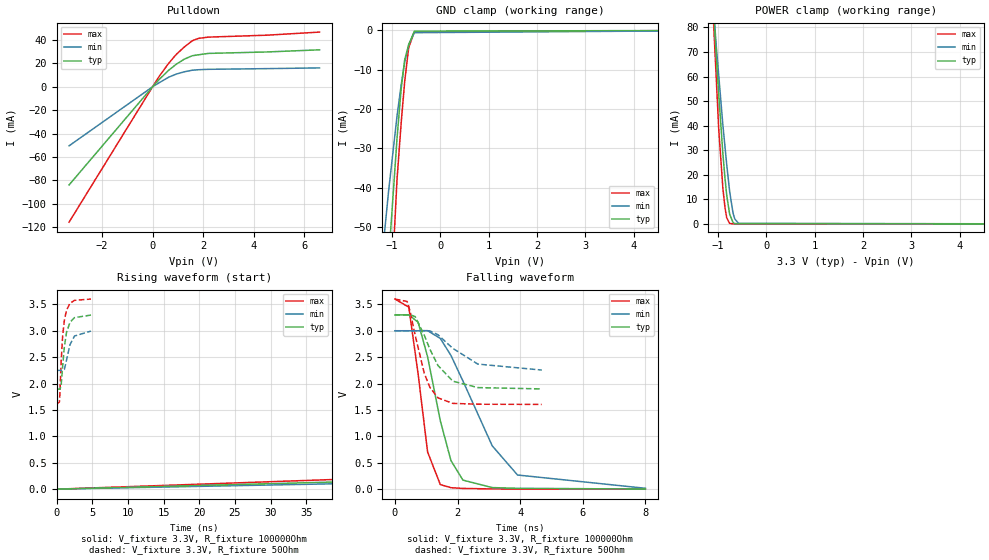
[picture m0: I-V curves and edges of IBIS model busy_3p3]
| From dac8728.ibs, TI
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|   busy_3p3 Model
[Model]   busy_3p3
Model_type   Open_drain
Polarity   Non-Inverting
Vmeas = 1.65
Vref = 3.3
Cref = 10pF
Rref = 100000
|   typ   min   max
|   (nom PVT)   (Fast PVT)   (slow PVT)
|C_comp from frequency method(F=50MHz)
|Average
C_comp   8.636e-12   7.116e-12   1.008e-11
|ON state : BUFFER OUTPUT TURNED LOW
|C_comp   8.804e-12   7.277e-12   1.026e-11
|OFF state: BUFFER IN HIGH IMPEDANCE
|C_comp   8.467e-12   6.956e-12   9.902e-12
|C_comp from L-C Tank method(L=1nH)
|Average
|C_comp   7.915e-12   6.670e-12   9.147e-12
|ON state : BUFFER OUTPUT TURNED LOW
|Resonant Frequency(Hz)   1.780e+09   1.930e+09   1.660e+09
|C_comp   8.003e-12   6.807e-12   9.201e-12
|OFF state: BUFFER IN HIGH IMPEDANCE
|Resonant Frequency(Hz)   1.800e+09   1.970e+09   1.670e+09
|C_comp   7.826e-12   6.533e-12   9.092e-12
| Where nom  PVT is Nominal Process,  3.3V,  33C
|   Fast PVT is Strong Process,   3.6V,  -40C
|   Slow PVT is Weak Process,   3V,  113C
[Voltage Range]   3.3   3   3.6
|Ambient Temperature   25   105   -40
|Junction Temperature
[Temperature Range]   33   113   -40
[Pullup Reference]   3.3   3   3.6
[Pulldown Reference]   0   0   0
[Power Clamp Reference]   3.3   3   3.6
[GND Clamp Reference]   0   0   0
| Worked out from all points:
|   slope of the pulldown table from 0 to 0.495 V, typ, clamps not added: 44 ohm
|   GND clamp passes 1 mA (typ) near -0.60 V on its own axis
|   POWER clamp passes 1 mA (typ) near -0.71 V on its own axis
|   falling waveform, V_fixture 3.3V, R_fixture 100000Ohm: 20-80 % time 725ps typ, 1.43ns min, 436ps max; typ from 3.3 V to 0.003 V
|   rising waveform, V_fixture 3.3V, R_fixture 100000Ohm: 20-80 % time 1.23us typ, 1.47us min, 1.01us max; typ from 0.001 V to 3.3 V
|   falling waveform, V_fixture 3.3V, R_fixture 50Ohm: 20-80 % time 710ps typ, 972ps min, 507ps max; typ from 3.3 V to 1.9 V
|   rising waveform, V_fixture 3.3V, R_fixture 50Ohm: 20-80 % time 708ps typ, 889ps min, 569ps max; typ from 1.9 V to 3.3 V
[Pulldown]
|   Voltage   I(typ)   I(min)   I(max)
-3.3V     -84.11mA   -50.56mA   -116mA
18mV      443.3uA    274.6uA    641.4uA
273.6mV   6.576mA    3.631mA    9.304mA
633.6mV   14.12mA    8.199mA    20.06mA
939.6mV   19.39mA    10.93mA    27.83mA
1.247V    23.62mA    12.83mA    33.99mA
1.566V    26.63mA    14.23mA    39.43mA
1.814V    27.44mA    14.64mA    41.5mA
2.203V    28.63mA    14.99mA    42.59mA
4.5V      29.86mA    15.58mA    44.23mA
6.6V      31.7mA     16.21mA    46.9mA
[GND Clamp]
|   Voltage   I(typ)   I(min)   I(max)
-3.3V     -572.7mA   -387.4mA   -802.2mA
-1.361V   -118.9mA   -77.73mA   -170.9mA
-1.272V   -100mA     -65.91mA   -143mA
-1.184V   -81.73mA   -55mA      -115.6mA
-1.071V   -59.2mA    -40.91mA   -81.77mA
-1.036V   -52.29mA   -37.09mA   -71.86mA
-896.4mV  -27.44mA   -21.78mA   -37.88mA
-811.8mV  -14.96mA   -13.98mA   -23.71mA
-738mV    -7.483mA   -8.126mA   -12.99mA
-655.2mV  -3.679mA   -3.589mA   -4.387mA
-537.9mV  -215.9uA   -600.8uA   -323.7uA
6.6V      0A         0A         0A
[POWER Clamp]
|   Voltage   I(typ)   I(min)   I(max)
-3.3V     869.3mA    734.6mA    1.044A
-1.084V   85.81mA    86.41mA    79.97mA
-1.032V   68.16mA    72.24mA    58.91mA
-982.8mV  52.97mA    60.65mA    38.83mA
-896.4mV  28.7mA     40.32mA    14.56mA
-853.2mV  18.73mA    31.56mA    6.771mA
-817.2mV  11.76mA    24.27mA    2.531mA
-756mV    3.952mA    13.19mA    210.4uA
-687mV    641.4uA    4.545mA    38.04uA
-651mV    146.4uA    2.075mA    32.51uA
-573mV    128.8uA    253uA      20.54uA
6.6V      0A         0A         0A
[Ramp]
R_load = 100000
|   typ   min   max
dV/dt_r   1.97809/1.23136e-06   1.796/1.46732e-06   2.15905/1.00462e-06
dV/dt_f   1.97921/7.27305e-10   1.7988/1.45405e-09   2.15938/4.41656e-10
[Falling Waveform]
V_fixture = 3.3V
V_fixture_min = 3V
V_fixture_max = 3.6V
R_fixture = 100000Ohm
|   Time   V(typ)   V(min)   V(max)
0s        3.3V       3V         3.6V
444ps     3.301V     3V         3.447V
742ps     3.161V     3V         2.182V
1.044ns   2.51V      3.002V     705.3mV
1.45ns    1.297V     2.855V     88.05mV
1.79ns    542.7mV    2.533V     28.73mV
2.172ns   172.7mV    2.05V      15.13mV
3.108ns   30.9mV     821.4mV    5.404mV
3.916ns   17.36mV    269mV      2.781mV
7.998ns   2.988mV    17.76mV    1.029mV
[Rising Waveform]
V_fixture = 3.3V
V_fixture_min = 3V
V_fixture_max = 3.6V
R_fixture = 100000Ohm
|   Time   V(typ)   V(min)   V(max)
0s        1.294mV    1.958mV    1.007mV
165.8ns   576.4mV    432.5mV    782mV
309.5ns   1.012V     774.2mV    1.331V
472.7ns   1.418V     1.108V     1.813V
648.3ns   1.765V     1.408V     2.202V
1.091us   2.361V     1.955V     2.819V
1.674us   2.788V     2.382V     3.212V
2.443us   3.055V     2.677V     3.435V
3.709us   3.223V     2.882V     3.557V
8us       3.298V     2.995V     3.599V
[Falling Waveform]
V_fixture = 3.3V
V_fixture_min = 3V
V_fixture_max = 3.6V
R_fixture = 50Ohm
|   Time   V(typ)   V(min)   V(max)
0s        3.3V       3V         3.6V
392ps     3.3V       3V         3.554V
488ps     3.302V     3V         3.366V
648ps     3.268V     3V         2.915V
940ps     2.913V     3.001V     2.191V
1.116ns   2.652V     2.998V     1.931V
1.376ns   2.342V     2.924V     1.73V
1.848ns   2.046V     2.667V     1.625V
2.648ns   1.924V     2.369V     1.609V
4.688ns   1.899V     2.256V     1.606V
[Rising Waveform]
V_fixture = 3.3V
V_fixture_min = 3V
V_fixture_max = 3.6V
R_fixture = 50Ohm
|   Time   V(typ)   V(min)   V(max)
0s        1.896V     2.249V     1.605V
404ps     1.894V     2.249V     1.652V
484ps     1.892V     2.249V     1.835V
648ps     1.962V     2.248V     2.416V
852ps     2.315V     2.244V     2.891V
1.1ns     2.701V     2.266V     3.201V
1.408ns   2.971V     2.447V     3.392V
1.892ns   3.16V      2.738V     3.52V
2.524ns   3.248V     2.9V       3.575V
4.828ns   3.296V     2.993V     3.599V
